VERSION 5.7 ;
  NOWIREEXTENSIONATPIN ON ;
  DIVIDERCHAR "/" ;
  BUSBITCHARS "[]" ;
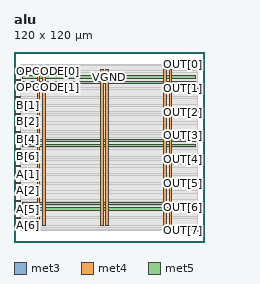
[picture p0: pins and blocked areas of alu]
MACRO alu
  CLASS BLOCK ;
  FOREIGN alu ;
  ORIGIN 0.000 0.000 ;
  SIZE 120.000 BY 120.000 ;
  PIN A[0]
    DIRECTION INPUT ;
    USE SIGNAL ;
    ANTENNAGATEAREA 0.159000 ;
    PORT
      LAYER met3 ;
        RECT 0.000 47.640 4.000 48.240 ;
    END
  END A[0]
  PIN A[1]
    DIRECTION INPUT ;
    USE SIGNAL ;
    ANTENNAGATEAREA 0.213000 ;
    PORT
      LAYER met3 ;
        RECT 0.000 42.200 4.000 42.800 ;
    END
  END A[1]
  PIN A[2]
    DIRECTION INPUT ;
    USE SIGNAL ;
    ANTENNAGATEAREA 0.213000 ;
    PORT
      LAYER met3 ;
        RECT 0.000 36.760 4.000 37.360 ;
    END
  END A[2]
  PIN A[3]
    DIRECTION INPUT ;
    USE SIGNAL ;
    ANTENNAGATEAREA 0.213000 ;
    PORT
      LAYER met3 ;
        RECT 0.000 31.320 4.000 31.920 ;
    END
  END A[3]
  PIN A[4]
    DIRECTION INPUT ;
    USE SIGNAL ;
    ANTENNAGATEAREA 0.213000 ;
    PORT
      LAYER met3 ;
        RECT 0.000 25.880 4.000 26.480 ;
    END
  END A[4]
  PIN A[5]
    DIRECTION INPUT ;
    USE SIGNAL ;
    ANTENNAGATEAREA 0.213000 ;
    PORT
      LAYER met3 ;
        RECT 0.000 20.440 4.000 21.040 ;
    END
  END A[5]
  PIN A[6]
    DIRECTION INPUT ;
    USE SIGNAL ;
    ANTENNAGATEAREA 0.126000 ;
    PORT
      LAYER met3 ;
        RECT 0.000 15.000 4.000 15.600 ;
    END
  END A[6]
  PIN A[7]
    DIRECTION INPUT ;
    USE SIGNAL ;
    ANTENNAGATEAREA 0.126000 ;
    PORT
      LAYER met3 ;
        RECT 0.000 9.560 4.000 10.160 ;
    END
  END A[7]
  PIN B[0]
    DIRECTION INPUT ;
    USE SIGNAL ;
    ANTENNAGATEAREA 0.159000 ;
    PORT
      LAYER met3 ;
        RECT 0.000 91.160 4.000 91.760 ;
    END
  END B[0]
  PIN B[1]
    DIRECTION INPUT ;
    USE SIGNAL ;
    ANTENNAGATEAREA 0.213000 ;
    PORT
      LAYER met3 ;
        RECT 0.000 85.720 4.000 86.320 ;
    END
  END B[1]
  PIN B[2]
    DIRECTION INPUT ;
    USE SIGNAL ;
    ANTENNAGATEAREA 0.213000 ;
    PORT
      LAYER met3 ;
        RECT 0.000 80.280 4.000 80.880 ;
    END
  END B[2]
  PIN B[3]
    DIRECTION INPUT ;
    USE SIGNAL ;
    ANTENNAGATEAREA 0.213000 ;
    PORT
      LAYER met3 ;
        RECT 0.000 74.840 4.000 75.440 ;
    END
  END B[3]
  PIN B[4]
    DIRECTION INPUT ;
    USE SIGNAL ;
    ANTENNAGATEAREA 0.213000 ;
    PORT
      LAYER met3 ;
        RECT 0.000 69.400 4.000 70.000 ;
    END
  END B[4]
  PIN B[5]
    DIRECTION INPUT ;
    USE SIGNAL ;
    ANTENNAGATEAREA 0.126000 ;
    PORT
      LAYER met3 ;
        RECT 0.000 63.960 4.000 64.560 ;
    END
  END B[5]
  PIN B[6]
    DIRECTION INPUT ;
    USE SIGNAL ;
    ANTENNAGATEAREA 0.196500 ;
    PORT
      LAYER met3 ;
        RECT 0.000 58.520 4.000 59.120 ;
    END
  END B[6]
  PIN B[7]
    DIRECTION INPUT ;
    USE SIGNAL ;
    ANTENNAGATEAREA 0.196500 ;
    PORT
      LAYER met3 ;
        RECT 0.000 53.080 4.000 53.680 ;
    END
  END B[7]
  PIN OPCODE[0]
    DIRECTION INPUT ;
    USE SIGNAL ;
    ANTENNAGATEAREA 0.196500 ;
    PORT
      LAYER met3 ;
        RECT 0.000 107.480 4.000 108.080 ;
    END
  END OPCODE[0]
  PIN OPCODE[1]
    DIRECTION INPUT ;
    USE SIGNAL ;
    ANTENNAGATEAREA 0.213000 ;
    PORT
      LAYER met3 ;
        RECT 0.000 102.040 4.000 102.640 ;
    END
  END OPCODE[1]
  PIN OPCODE[2]
    DIRECTION INPUT ;
    USE SIGNAL ;
    ANTENNAGATEAREA 0.213000 ;
    PORT
      LAYER met3 ;
        RECT 0.000 96.600 4.000 97.200 ;
    END
  END OPCODE[2]
  PIN OUT[0]
    DIRECTION OUTPUT ;
    USE SIGNAL ;
    ANTENNADIFFAREA 0.445500 ;
    PORT
      LAYER met3 ;
        RECT 116.000 111.560 120.000 112.160 ;
    END
  END OUT[0]
  PIN OUT[1]
    DIRECTION OUTPUT ;
    USE SIGNAL ;
    ANTENNADIFFAREA 0.445500 ;
    PORT
      LAYER met3 ;
        RECT 116.000 96.600 120.000 97.200 ;
    END
  END OUT[1]
  PIN OUT[2]
    DIRECTION OUTPUT ;
    USE SIGNAL ;
    ANTENNADIFFAREA 0.445500 ;
    PORT
      LAYER met3 ;
        RECT 116.000 81.640 120.000 82.240 ;
    END
  END OUT[2]
  PIN OUT[3]
    DIRECTION OUTPUT ;
    USE SIGNAL ;
    ANTENNADIFFAREA 0.445500 ;
    PORT
      LAYER met3 ;
        RECT 116.000 66.680 120.000 67.280 ;
    END
  END OUT[3]
  PIN OUT[4]
    DIRECTION OUTPUT ;
    USE SIGNAL ;
    ANTENNADIFFAREA 0.445500 ;
    PORT
      LAYER met3 ;
        RECT 116.000 51.720 120.000 52.320 ;
    END
  END OUT[4]
  PIN OUT[5]
    DIRECTION OUTPUT ;
    USE SIGNAL ;
    ANTENNADIFFAREA 0.445500 ;
    PORT
      LAYER met3 ;
        RECT 116.000 36.760 120.000 37.360 ;
    END
  END OUT[5]
  PIN OUT[6]
    DIRECTION OUTPUT ;
    USE SIGNAL ;
    ANTENNADIFFAREA 0.445500 ;
    PORT
      LAYER met3 ;
        RECT 116.000 21.800 120.000 22.400 ;
    END
  END OUT[6]
  PIN OUT[7]
    DIRECTION OUTPUT ;
    USE SIGNAL ;
    ANTENNADIFFAREA 0.445500 ;
    PORT
      LAYER met3 ;
        RECT 116.000 6.840 120.000 7.440 ;
    END
  END OUT[7]
  PIN VGND
    DIRECTION INOUT ;
    USE GROUND ;
    PORT
      LAYER met4 ;
        RECT 18.020 10.640 19.620 109.040 ;
    END
    PORT
      LAYER met4 ;
        RECT 58.020 10.640 59.620 109.040 ;
    END
    PORT
      LAYER met4 ;
        RECT 98.020 10.640 99.620 109.040 ;
    END
    PORT
      LAYER met5 ;
        RECT 5.280 23.380 114.320 24.980 ;
    END
    PORT
      LAYER met5 ;
        RECT 5.280 63.380 114.320 64.980 ;
    END
    PORT
      LAYER met5 ;
        RECT 5.280 103.380 114.320 104.980 ;
    END
  END VGND
  PIN VPWR
    DIRECTION INOUT ;
    USE POWER ;
    PORT
      LAYER met4 ;
        RECT 14.720 10.640 16.320 109.040 ;
    END
    PORT
      LAYER met4 ;
        RECT 54.720 10.640 56.320 109.040 ;
    END
    PORT
      LAYER met4 ;
        RECT 94.720 10.640 96.320 109.040 ;
    END
    PORT
      LAYER met5 ;
        RECT 5.280 20.080 114.320 21.680 ;
    END
    PORT
      LAYER met5 ;
        RECT 5.280 60.080 114.320 61.680 ;
    END
    PORT
      LAYER met5 ;
        RECT 5.280 100.080 114.320 101.680 ;
    END
  END VPWR
  OBS
      LAYER nwell ;
        RECT 5.330 10.795 114.270 108.885 ;
      LAYER li1 ;
        RECT 5.520 10.795 114.080 108.885 ;
      LAYER met1 ;
        RECT 4.210 10.640 114.080 109.040 ;
      LAYER met2 ;
        RECT 4.230 6.955 112.150 112.045 ;
      LAYER met3 ;
        RECT 3.990 111.160 115.600 112.025 ;
        RECT 3.990 108.480 116.000 111.160 ;
        RECT 4.400 107.080 116.000 108.480 ;
        RECT 3.990 103.040 116.000 107.080 ;
        RECT 4.400 101.640 116.000 103.040 ;
        RECT 3.990 97.600 116.000 101.640 ;
        RECT 4.400 96.200 115.600 97.600 ;
        RECT 3.990 92.160 116.000 96.200 ;
        RECT 4.400 90.760 116.000 92.160 ;
        RECT 3.990 86.720 116.000 90.760 ;
        RECT 4.400 85.320 116.000 86.720 ;
        RECT 3.990 82.640 116.000 85.320 ;
        RECT 3.990 81.280 115.600 82.640 ;
        RECT 4.400 81.240 115.600 81.280 ;
        RECT 4.400 79.880 116.000 81.240 ;
        RECT 3.990 75.840 116.000 79.880 ;
        RECT 4.400 74.440 116.000 75.840 ;
        RECT 3.990 70.400 116.000 74.440 ;
        RECT 4.400 69.000 116.000 70.400 ;
        RECT 3.990 67.680 116.000 69.000 ;
        RECT 3.990 66.280 115.600 67.680 ;
        RECT 3.990 64.960 116.000 66.280 ;
        RECT 4.400 63.560 116.000 64.960 ;
        RECT 3.990 59.520 116.000 63.560 ;
        RECT 4.400 58.120 116.000 59.520 ;
        RECT 3.990 54.080 116.000 58.120 ;
        RECT 4.400 52.720 116.000 54.080 ;
        RECT 4.400 52.680 115.600 52.720 ;
        RECT 3.990 51.320 115.600 52.680 ;
        RECT 3.990 48.640 116.000 51.320 ;
        RECT 4.400 47.240 116.000 48.640 ;
        RECT 3.990 43.200 116.000 47.240 ;
        RECT 4.400 41.800 116.000 43.200 ;
        RECT 3.990 37.760 116.000 41.800 ;
        RECT 4.400 36.360 115.600 37.760 ;
        RECT 3.990 32.320 116.000 36.360 ;
        RECT 4.400 30.920 116.000 32.320 ;
        RECT 3.990 26.880 116.000 30.920 ;
        RECT 4.400 25.480 116.000 26.880 ;
        RECT 3.990 22.800 116.000 25.480 ;
        RECT 3.990 21.440 115.600 22.800 ;
        RECT 4.400 21.400 115.600 21.440 ;
        RECT 4.400 20.040 116.000 21.400 ;
        RECT 3.990 16.000 116.000 20.040 ;
        RECT 4.400 14.600 116.000 16.000 ;
        RECT 3.990 10.560 116.000 14.600 ;
        RECT 4.400 9.160 116.000 10.560 ;
        RECT 3.990 7.840 116.000 9.160 ;
        RECT 3.990 6.975 115.600 7.840 ;
  END
END alu
END LIBRARY

